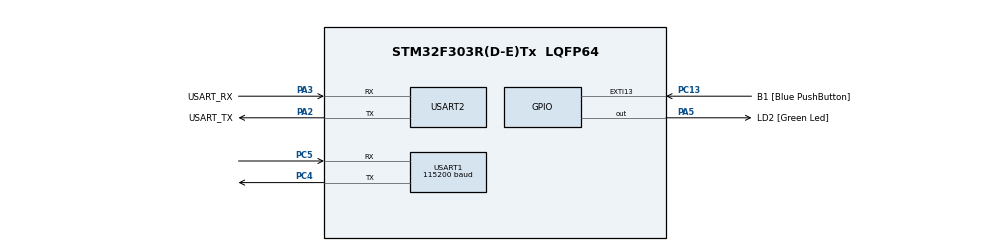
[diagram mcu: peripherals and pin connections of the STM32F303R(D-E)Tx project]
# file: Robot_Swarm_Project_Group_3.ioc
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Mcu.Family=STM32F3
Mcu.Name=STM32F303R(D-E)Tx
Mcu.Package=LQFP64
NVIC.PriorityGroup=NVIC_PRIORITYGROUP_0
NVIC.USART1_IRQn=true\:0\:0\:false\:false\:true\:true\:true\:true
PA13.GPIO_Label=TMS
PA13.Mode=Serial_Wire
PA13.Signal=SYS_JTMS-SWDIO
PA14.GPIO_Label=TCK
PA14.Mode=Serial_Wire
PA14.Signal=SYS_JTCK-SWCLK
PA2.GPIO_Label=USART_TX
PA2.GPIO_Mode=GPIO_MODE_AF_PP
PA2.GPIO_PuPd=GPIO_NOPULL
PA2.GPIO_Speed=GPIO_SPEED_FREQ_LOW
PA2.Mode=Asynchronous
PA2.Signal=USART2_TX
PA3.GPIO_Label=USART_RX
PA3.GPIO_Mode=GPIO_MODE_AF_PP
PA3.GPIO_PuPd=GPIO_NOPULL
PA3.GPIO_Speed=GPIO_SPEED_FREQ_LOW
PA3.Mode=Asynchronous
PA3.Signal=USART2_RX
PA5.GPIO_Label=LD2 [Green Led]
PA5.GPIO_Mode=GPIO_MODE_OUTPUT_PP
PA5.GPIO_PuPd=GPIO_NOPULL
PA5.GPIO_Speed=GPIO_SPEED_FREQ_LOW
PA5.Signal=GPIO_Output
PB3.GPIO_Label=SWO
PB3.Signal=SYS_JTDO-TRACESWO
PC13.GPIO_Label=B1 [Blue PushButton]
PC13.GPIO_ModeDefaultEXTI=GPIO_MODE_IT_FALLING
PC13.Signal=GPXTI13
PC14-OSC32_IN.Mode=LSE-External-Oscillator
PC14-OSC32_IN.Signal=RCC_OSC32_IN
PC15-OSC32_OUT.Mode=LSE-External-Oscillator
PC15-OSC32_OUT.Signal=RCC_OSC32_OUT
PC4.Mode=Asynchronous
PC4.Signal=USART1_TX
PC5.Mode=Asynchronous
PC5.Signal=USART1_RX
PF0-OSC_IN.Mode=HSE-External-Clock-Source
PF0-OSC_IN.Signal=RCC_OSC_IN
PF1-OSC_OUT.Signal=RCC_OSC_OUT
ProjectManager.HeapSize=0x200
ProjectManager.StackSize=0x400
ProjectManager.TargetToolchain=STM32CubeIDE
RCC.AHBFreq_Value=16000000
RCC.APB1CLKDivider=RCC_HCLK_DIV2
RCC.APB1Freq_Value=8000000
RCC.APB1TimFreq_Value=16000000
RCC.APB2Freq_Value=16000000
RCC.APB2TimFreq_Value=16000000
RCC.CortexFreq_Value=16000000
RCC.HCLKFreq_Value=16000000
RCC.HSE_VALUE=8000000
RCC.HSI_VALUE=8000000
RCC.PLLM=8
RCC.PLLN=336
RCC.PLLP=RCC_PLLP_DIV4
RCC.PLLQ=7
RCC.RCC_PLLsource_Clock_Source_FROM_HSE=RCC_HSE_PREDIV_DIV2
RCC.SYSCLKFreq_VALUE=16000000
RCC.SYSCLKSourceVirtual=RCC_SYSCLKSOURCE_PLLCLK
RCC.USBFreq_Value=16000000
USART1.BaudRate=115200
USART1.VirtualMode-Asynchronous=VM_ASYNC
USART2.VirtualMode-Asynchronous=VM_ASYNC
board=NUCLEO-F303RE

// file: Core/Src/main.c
/* USER CODE BEGIN Header */
/**
  ******************************************************************************
  * @file           : main.c
  * @brief          : Main program body
  ******************************************************************************
  * @attention
  *
  * Copyright (c) 2022 STMicroelectronics.
  * All rights reserved.
  *
  * This software is licensed under terms that can be found in the LICENSE file
  * in the root directory of this software component.
  * If no LICENSE file comes with this software, it is provided AS-IS.
  *
  ******************************************************************************
  */
/* USER CODE END Header */
#include "main.h"

/* USER CODE BEGIN Includes */
#include "library.h"
/* USER CODE END Includes */

/* USER CODE BEGIN PD */
# define UART_INT 1000
/* USER CODE END PD */

/* USER CODE BEGIN PM */
enum direction{
	LEFT,
	RIGHT,
};
# define RAND_LIMIT 2
/* USER CODE END PM */

UART_HandleTypeDef huart1;
UART_HandleTypeDef huart2;

void SystemClock_Config(void);
static void MX_GPIO_Init(void);
static void MX_USART2_UART_Init(void);
static void MX_USART1_UART_Init(void);
/* USER CODE BEGIN PFP */
int UART_transmit(int);
HAL_StatusTypeDef read_status();

int32_t distance = 0;
uint64_t last_transmit_UART = 0;

// servo values after PID added
double left_wheel = 0;
double right_wheel = 0;

// servo current values
uint32_t left_val = 0;
uint32_t right_val = 0;

// PID simulated values
double KP = 1.0001;
double KI = 0.1825;
double KD = 0.1887;

// PID function variables
double calcpid = 0;
double PID_output = 0;
double prev_error = 0;
double derivative = 0;
int set_point = 50;	// 20cm
int error = 0;
uint8_t rxChar;

// Ultrasonic wall distance function
bool no_wall(uint32_t distance)
{
	return ((distance > 2) &&(distance <= 6));
}

/* USER CODE END PFP */

/* USER CODE BEGIN 0 */
int UART_transmit(int value)
{
	char txBuf[80] = {0};
	USART1->ICR |= USART_ICR_ORECF; // Clear the overrun error bit.
	snprintf(txBuf, sizeof(txBuf), " %d\n", value);
	HAL_StatusTypeDef status;
	status = HAL_UART_Transmit(&huart1, (uint8_t *)txBuf, strlen(txBuf), 10);
	return status;
}

HAL_StatusTypeDef read_status()
{
	USART1->ICR |= USART_ICR_ORECF; // Clear the overrun error bit.
	HAL_StatusTypeDef status;
	// Set timeout to 0 so it will not block,
	// just read one character if available.
	status = HAL_UART_Receive(&huart1, (uint8_t*)&rxChar, 1, 0);//IT(&huart3, &rxChar, 1);
	return status;
}
/* USER CODE END 0 */

int main(void)
{

  /* MCU Configuration--------------------------------------------------------*/

  /* Reset of all peripherals, Initializes the Flash interface and the Systick. */
  HAL_Init();

  /* Configure the system clock */
  SystemClock_Config();

  /* Initialize all configured peripherals */
  MX_GPIO_Init();
  MX_USART2_UART_Init();
  MX_USART1_UART_Init();
  /* USER CODE BEGIN 2 */
	RCC->AHBENR|= RCC_AHBENR_GPIOAEN | RCC_AHBENR_GPIOBEN;			// Enable GPIO bus
	SetPin(GPIOB, 3, ALTFUNCTMODE, PUSHPULL, LOWSPEED, NOPULL);		// (PB3)D3 Timer 2 PIN Config LEFT WHEEL
	SetPin(GPIOA, 0, ALTFUNCTMODE, PUSHPULL, LOWSPEED, NOPULL);		// (PA0)A0 Timer 2 PIN Config RIGHT WHEEL
	SetPin(GPIOA, 5, OUTPUT, PUSHPULL, LOWSPEED, NOPULL);			// LED test

	CMR_TIM2_config();												// Timer 2 SERVO Config

	SetPin(GPIOB, 5, ALTFUNCTMODE, PUSHPULL, LOWSPEED, NOPULL);		// (PB5)D4 Timer 3 TRIGGER Config
	CMR_TIM3_config();												// Timer 3 TRIGGER Config

	SetPin(GPIOB, 6, ALTFUNCTMODE, PUSHPULL, LOWSPEED, NOPULL);		// (PB6)D10 Timer 4 ECHO Config
	CMR_TIM4_config();												// Timer 4 ECHO Config
  INIT_RAND(RAND_LIMIT);
  urand_t rand_direction = 0;

  /* USER CODE END 2 */

  /* Infinite loop */
  /* USER CODE BEGIN WHILE */
  while (1)
  {
	  distance = ((TIM4->CCR2)/58);
	  distance -= 38;

	  if(HAL_GetTick() - last_transmit_UART >= UART_INT)
	  {
		  last_transmit_UART = HAL_GetTick();
		  UART_transmit(distance);
	  }

	  if(read_status() == HAL_OK)
	  {
		  set_point = rxChar;
	  }

	  PID_output = myPID(distance, set_point, KP, KD);
	  left_wheel = map(PID_output, 0, 100, 178, 187);	// Used to map servo speed into 0 to 100%
	  right_wheel = map(PID_output, 0, 100, 162, 151);
	if (no_wall(distance))	// condition activates when it reaches 10cm
	{
		servo_pwm(0, 0);				// first param left wheel PB3. second param right wheel PA0. (FULLSTOP)
		HAL_Delay(1000);

		// Good shit
		rand_direction = Get_Random_NoU();
		// Now use this shit of a random generated direction no
		switch (rand_direction) {
			case LEFT:{
				// Put code to move to the left
				servo_pwm(151, 0);
				HAL_Delay(1250);
				servo_pwm(0, 151);				// first param left wheel PB3. second param right wheel PA0. (TURN LEFT)
				break;
			}
			case RIGHT:{
				// Put the code to move to the right
				servo_pwm(0, 187);
				HAL_Delay(1250);
				servo_pwm(187, 0);				// first param left wheel PB3. second param right wheel PA0. (TURN RIGHT)
				break;
			}
		}
	}
	else if (no_wall(distance) == false)
	{
		servo_pwm(left_wheel, right_wheel);		// first param left wheel PB3. second param right wheel PA0. (STRAIGHT)
	}
    /* USER CODE END WHILE */

  }
}

void SystemClock_Config(void)
{
	  RCC_OscInitTypeDef RCC_OscInitStruct = {0};
	  RCC_ClkInitTypeDef RCC_ClkInitStruct = {0};
	  RCC_PeriphCLKInitTypeDef PeriphClkInit = {0};

	  /** Initializes the RCC Oscillators according to the specified parameters
	  * in the RCC_OscInitTypeDef structure.
	  */
	  RCC_OscInitStruct.OscillatorType = RCC_OSCILLATORTYPE_HSI;
	  RCC_OscInitStruct.HSIState = RCC_HSI_ON;
	  RCC_OscInitStruct.HSICalibrationValue = RCC_HSICALIBRATION_DEFAULT;
	  RCC_OscInitStruct.PLL.PLLState = RCC_PLL_ON;
	  RCC_OscInitStruct.PLL.PLLSource = RCC_PLLSOURCE_HSI;
	  RCC_OscInitStruct.PLL.PLLMUL = RCC_PLL_MUL9;
	  RCC_OscInitStruct.PLL.PREDIV = RCC_PREDIV_DIV1;
	  if (HAL_RCC_OscConfig(&RCC_OscInitStruct) != HAL_OK)
	  {
	    Error_Handler();
	  }

	  /** Initializes the CPU, AHB and APB buses clocks
	  */
	  RCC_ClkInitStruct.ClockType = RCC_CLOCKTYPE_HCLK|RCC_CLOCKTYPE_SYSCLK
	                              |RCC_CLOCKTYPE_PCLK1|RCC_CLOCKTYPE_PCLK2;
	  RCC_ClkInitStruct.SYSCLKSource = RCC_SYSCLKSOURCE_PLLCLK;
	  RCC_ClkInitStruct.AHBCLKDivider = RCC_SYSCLK_DIV1;
	  RCC_ClkInitStruct.APB1CLKDivider = RCC_HCLK_DIV2;
	  RCC_ClkInitStruct.APB2CLKDivider = RCC_HCLK_DIV1;

	  if (HAL_RCC_ClockConfig(&RCC_ClkInitStruct, FLASH_LATENCY_2) != HAL_OK)
	  {
	    Error_Handler();
	  }
	  PeriphClkInit.PeriphClockSelection = RCC_PERIPHCLK_USART2;
	  PeriphClkInit.Usart2ClockSelection = RCC_USART2CLKSOURCE_PCLK1;
	  if (HAL_RCCEx_PeriphCLKConfig(&PeriphClkInit) != HAL_OK)
	  {
	    Error_Handler();
	  }
}

static void MX_USART1_UART_Init(void)
{

  huart1.Instance = USART1;
  huart1.Init.BaudRate = 115200;
  huart1.Init.WordLength = UART_WORDLENGTH_8B;
  huart1.Init.StopBits = UART_STOPBITS_1;
  huart1.Init.Parity = UART_PARITY_NONE;
  huart1.Init.Mode = UART_MODE_TX_RX;
  huart1.Init.HwFlowCtl = UART_HWCONTROL_NONE;
  huart1.Init.OverSampling = UART_OVERSAMPLING_16;
  huart1.Init.OneBitSampling = UART_ONE_BIT_SAMPLE_DISABLE;
  huart1.AdvancedInit.AdvFeatureInit = UART_ADVFEATURE_NO_INIT;
  if (HAL_UART_Init(&huart1) != HAL_OK)
  {
    Error_Handler();
  }

}

static void MX_USART2_UART_Init(void)
{

  huart2.Instance = USART2;
  huart2.Init.BaudRate = 38400;
  huart2.Init.WordLength = UART_WORDLENGTH_8B;
  huart2.Init.StopBits = UART_STOPBITS_1;
  huart2.Init.Parity = UART_PARITY_NONE;
  huart2.Init.Mode = UART_MODE_TX_RX;
  huart2.Init.HwFlowCtl = UART_HWCONTROL_NONE;
  huart2.Init.OverSampling = UART_OVERSAMPLING_16;
  huart2.Init.OneBitSampling = UART_ONE_BIT_SAMPLE_DISABLE;
  huart2.AdvancedInit.AdvFeatureInit = UART_ADVFEATURE_NO_INIT;
  if (HAL_UART_Init(&huart2) != HAL_OK)
  {
    Error_Handler();
  }

}

static void MX_GPIO_Init(void)
{
  GPIO_InitTypeDef GPIO_InitStruct = {0};

  /* GPIO Ports Clock Enable */
  __HAL_RCC_GPIOC_CLK_ENABLE();
  __HAL_RCC_GPIOF_CLK_ENABLE();
  __HAL_RCC_GPIOA_CLK_ENABLE();
  __HAL_RCC_GPIOB_CLK_ENABLE();

  /*Configure GPIO pin Output Level */
  HAL_GPIO_WritePin(LD2_GPIO_Port, LD2_Pin, GPIO_PIN_RESET);

  /*Configure GPIO pin : B1_Pin */
  GPIO_InitStruct.Pin = B1_Pin;
  GPIO_InitStruct.Mode = GPIO_MODE_IT_FALLING;
  GPIO_InitStruct.Pull = GPIO_NOPULL;
  HAL_GPIO_Init(B1_GPIO_Port, &GPIO_InitStruct);

  /*Configure GPIO pin : LD2_Pin */
  GPIO_InitStruct.Pin = LD2_Pin;
  GPIO_InitStruct.Mode = GPIO_MODE_OUTPUT_PP;
  GPIO_InitStruct.Pull = GPIO_NOPULL;
  GPIO_InitStruct.Speed = GPIO_SPEED_FREQ_LOW;
  HAL_GPIO_Init(LD2_GPIO_Port, &GPIO_InitStruct);

}

void Error_Handler(void)
{
  __disable_irq();
  while (1)
  {
  }
}
